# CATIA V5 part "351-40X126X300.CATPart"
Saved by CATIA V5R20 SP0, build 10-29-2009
Part number: 351-40X126X300
Definition: NONE
Nomenclature: 351-40X126X300
Source: Unknown
Description: 351-40X126X300
Bounding box of the stored display mesh (mm): x -8 to 292, y -26 to 26, z -26 to 26
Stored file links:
  C:\Users\Utente\Desktop\IO LAVORO\3D X SITO CF\X SITO\PLASTICA\351\351-40X126X300.CATPart

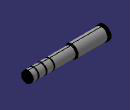
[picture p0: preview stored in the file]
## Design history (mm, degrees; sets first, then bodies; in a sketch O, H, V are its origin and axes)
Body1 "351-40X126X300" (main body)
  Solid1: solid without history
